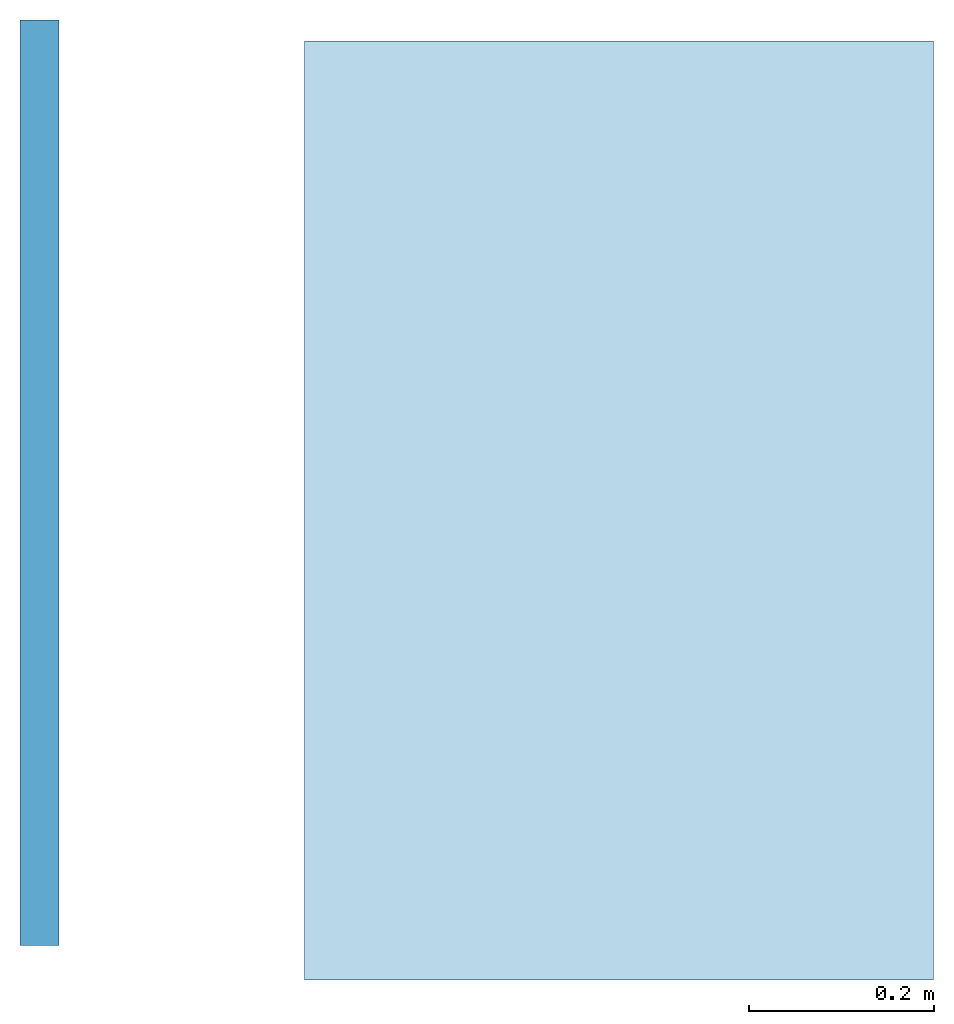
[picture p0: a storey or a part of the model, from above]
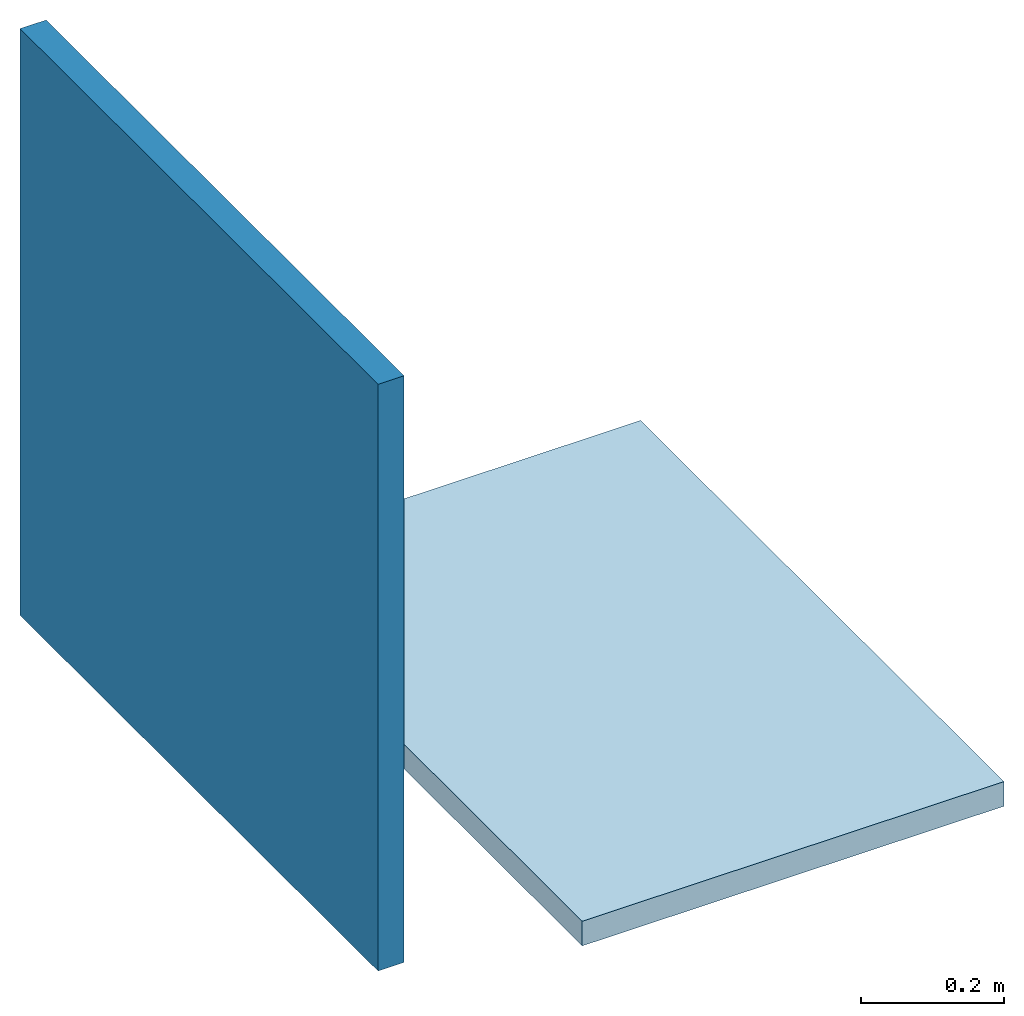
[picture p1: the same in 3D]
Properties of the parts of a building model (IFC2X3)

# File
Description: ViewDefinition [CoordinationView_V2.0]
File name: 0001
Time: 2017-06-13T11:19:18
Written by: The EXPRESS Data Manager Version 5.02.0100.07 : 28 Aug 2013
Made in: 20170223_1515(x64) - Exporter 18.0.0.420 - Alternate UI 18.0.0.420
Comment: STEP Physical File produced by: The EXPRESS Data Manager Version 5.02.0100.07 : 28 Aug 2013 * Module: EDMstepFileFactory/EDMstandAlone * Creation date: Tue Jun 13 11:19:18 2017 * Host: JAVIER * Database: C:\Users\JAVIER~1.DOM\AppData\Local\Temp\{FDAF7FB0-3CD8-4E24-841C-1A4DC4456FC2}\ifc * Database version: 5507 * Database creation date: Tue Jun 13 11:19:18 2017 * Schema: IFC2X3 * Model: DataRepository.ifc * Model creation date: Tue Jun 13 11:19:18 2017 * Header model: DataRepository.ifc_HeaderModel * Header model creation date: Tue Jun 13 11:19:18 2017 * EDMuser: sdai-user * EDMgroup: sdai-group * License ID and type: 5605 : Permanent license. Expiry date: * EDMstepFileFactory options: 020000

# IfcProject, 0001
LongName: Nombre de proyecto; Phase: Estado de proyecto

# IfcSite, Default
RefLatitude: 40, 24, 0, 5493; RefLongitude: -3, -40, -59, -880065; RefElevation: 0 m

# IfcBuilding
Pset_BuildingCommon - NumberOfStoreys: 1

# IfcBuildingStorey, Nivel 1
LongName: Nivel 1; Elevation: 0 m

# IfcSlab: Suelo:Grafipol® TR-5_Suelos_1015x680x42mm, Suelo:Grafipol® TR-5_Suelos_1015x680x42mm:168357
In: Nivel 1
PredefinedType: FLOOR; Classification: B Shell (Uniformat); Material: VALERO Grafipol® TR-5 0.042 m
Pset_SlabCommon - LoadBearing: no; IsExternal: no; Reference: Grafipol® TR-5_Suelos_1015x680x42mm; ThermalTransmittance: 0.785714 kg/K/s3; PitchAngle: 0 deg
Pset_ManufacturerTypeInformation - Manufacturer: Grupo Valero - José Manuel Valero, S. L.

# IfcWallStandardCase: Muro básico:Grafipol TR-5_Tabiques_1015x680x42mm, Muro básico:Grafipol TR-5_Tabiques_1015x680x42mm:166317
In: Nivel 1
Type - PredefinedType: STANDARD; Material: VALERO Grafipol® TR-5 0.042 m
Pset_WallCommon - Reference: Grafipol TR-5_Tabiques_1015x680x42mm; LoadBearing: no; ExtendToStructure: no; IsExternal: no; FireRating: E; ThermalTransmittance: 0.785714 kg/K/s3
Pset_ManufacturerTypeInformation - Manufacturer: Grupo Valero - José Manuel Valero, S. L.
